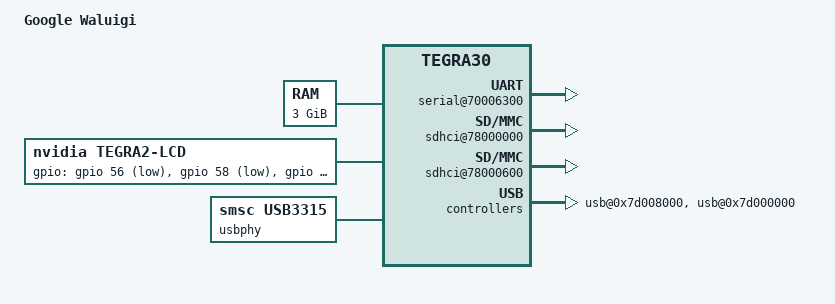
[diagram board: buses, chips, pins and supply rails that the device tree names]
/dts-v1/;

/memreserve/ 0x1c000000 0x04000000;
/include/ "../../../arch/arm/cpu/armv7/tegra3/tegra30.dtsi"

/ {
	model = "Google Waluigi";
	compatible = "google,waluigi", "nvidia,tegra30";

	config {
		silent_console = <0>;
		odmdata = <0x300d8011>;
		hwid = "ARM WALUIGI TEST 6666";
	};

	aliases {
		console = "/serial@70006300";
                usb0 = "/usb@0x7d000000";
                usb1 = "/usb@0x7d008000";

		sdmmc0 = "/sdhci@78000600";
		sdmmc1 = "/sdhci@78000000";

		kbc0 = "/kbc@0x7000e200";
	};

	chosen {
		bootargs = "";
	};

	memory {
		device_type = "memory";
		reg = <0x80000000 0xc0000000>;
	};

	serial@70006300 {
		status = "ok";
		/*
		 * TBD - use CONFIG_SYS_PLLP_BASE_IS_408MHZ somehow here.
		 * Currently I put this back to 216MHz in fdt_decode.c
		 */
		clock-frequency = <408000000>;
	};

	sdhci@78000000 {
		status = "ok";
		width = <4>;	/* width of SDIO port */
		removable = <1>;
		/* Parameter 3 bit 0:1=output, 0=input; bit 1:1=high, 0=low */
		cd-gpio = <&gpio 69 0>; /* card detect, gpio PI5 */
		wp-gpio = <&gpio 155 0>; /* write protect, gpio PT3 */
		power-gpio = <&gpio 31 3>; /* power enable, gpio PD7 */
	};

	sdhci@78000600 {
		status = "ok";
		width = <4>;	/* width of SDIO port */
		removable = <0>;
		power-gpio = <&gpio 25 3>; /* power enable, gpio PD1 */
	};

	lcd {
		compatible = "nvidia,tegra2-lcd";
		width = <1280>;
		height = <800>;
		bits_per_pixel = <16>;
		pwfm = <&pwfm0>;
		display = <&display1>;
		frame-buffer = <0x1C022000>;

		pixel_clock = <68000000>;

		/* Timing: ref_to_sync, sync_width. back_porch, front_porch */
		horiz_timing = <0 30 52 64>;
		vert_timing = <12 5 20 25>;

		/* Parameter 3 bit 0:1=output, 0=input; bit 1:1=high, 0=low */
		gpios = <&gpio 56 3>,	/* PH0, LCD1_BL_PWM */
			<&gpio 58 3>,	/* PH2, LCD1_BL_EN */
			<&gpio 90 3>,	/* PL2, LVDS1_SHTDN */
			<&gpio 92 3>;	/* PL4, EN_VDD_PNL1 */
	};

	usb@0x7d008000 {
		status = "ok";
		host-mode = <1>;
	};

	usbphy: usbphy@0 {
		compatible = "smsc,usb3315";
		status = "ok";
	};

	usb@0x7d000000 {
		status = "ok";
		utmi = <&usbphy>;
		host-mode = <0>;

		/* Third value bit 0=1 output, 0 input; bit 1=1 high, 0 low */
		vbus-gpio = <&gpio 238 0>;
		vbus_pullup-gpio = <&gpio 233 3>;
	};

        kbc@0x7000e200 {
        keycode-plain    = [00  00  DD  00  DC  00  00  00
                            0f  1B  09  '`' 'a' 'z' '1' 'q'
                            f1  f4  f3  f2  'd' 'c' '3' 'e'
                            00  00  00  00  00  00  00  00
                            'b' 'g' 't' '5' 'f' 'v' '4' 'r'
                            FA  F7  F6  f5  's' 'x' '2' 'w'
                            0f  00  ']' 00  'k' ',' '8' 'i'
                            00  00  00  00  00  00  00  00
                            'n' 'h' 'y' '6' 'j' 'm' '7' 'u'
                            00  00  0f  00  00  DF  00  DF
                            '=' 2C  '[' '-' ';' '/' '0' 'p'
                            00  f9  f8  00  'l' '.' '9' 'o'
                            00  00  00  00  00  00  00  00
                            0f  00  0f  00  00  00  0f  00
                            00  08  00  5C  0D  ' ' 0f  0f
                            00  0f  00  0f  00  00  0f  0f];

        keycode-shift    = [00  00  0F  00  0f  00  00  00
                            0f  1B  00  '~' 'A' 'Z' '!' 'Q'
                            f1  f4  f3  f2  'D' 'C' '#' 'E'
                            00  00  00  00  00  00  00  00
                            'B' 'G' 'T' '%' 'F' 'V' '$' 'R'
                            0A  07  06  05  'S' 'X' '@' 'W'
                            0f  00  '}' 00  'K' '<' '*' 'I'
                            00  00  00  00  00  00  00  00
                            'N' 'H' 'Y' '^' 'J' 'M' '&' 'U'
                            00  00  0f  00  00  0f  00  0f
                            '+' '"' '{' '_' ':' '?' ')' 'P'
                            00  f9  f8  00  'L' '>' '(' 'O'
                            00  00  00  00  00  00  00  00
                            0f  00  0f  00  00 00  0f  00
                            00  08  00  '|' 0f  ' ' 0f  0f
                            00  0f  00  0f  00  00  0f  0f];

        keycode-fn       = [00  00  00  00  00  00  00  00
                            00  00  00  00  00  00  00  00
                            00  00  00  00  00  00  00  00
                            00  00  00  00  00  00  00  00
                            00  00  00  00  00  00  00  00
                            00  00  00  00  00  00  00  00
                            00  00  00  00  00  00  00  00
                            00  00  00  00  00  00  00  00
                            00  00  00  00  00  00  00  00
                            00  00  00  00  00  00  00  00
                            00  00  00  00  00  00  00  00
                            00  00  00  00  00  00  00  00
                            00  00  00  00  00  00  00  00
                            00  00  00  00  00  00  00  00
                            00  00  00  00  00  00  00  00
                            00  00  00  00  00  00  00  00];

        keycode-ctrl     = [00  00  00  00  00  00  00  00
                            00  00  00  00  01  1A  00  11
                            00  00  00  00  04  03  00  05
                            00  00  00  00  00  00  00  00
                            02  07  14  00  06  16  00  12
                            00  00  00  00  13  18  00  17
                            00  00  00  00  0B  00  00  09
                            00  00  00  00  00  00  00  00
                            0E  08  19  00  0A  00  00  15
                            00  00  00  00  00  00  00  00
                            00  00  00  00  00  00  00  10
                            00  00  00  00  0C  00  00  0F
                            00  00  00  00  00  00  00  00
                            00  00  00  00  00  00  00  00
                            00  00  00  00  00  00  00  00
                            00  00  00  00  00  00  00  00];
        };

};
